# ICPS2023_5 experimental 1M routing stack for LibreLane/OpenROAD only.
# POLY and narrow TiN dimensions/R values are user-directed hypotheses, not
# foundry-qualified geometry. See libs.tech/librelane/README.md.
VERSION 5.8 ;
BUSBITCHARS "[]" ;
DIVIDERCHAR "/" ;
UNITS
  DATABASE MICRONS 1000 ;
END UNITS
MANUFACTURINGGRID 0.001 ;
# The selected row origin matches the largest published standard cell (700 um
# high); the SCL cell LEFs use this exact site name.
SITE ICPS2023_5_ROW700
  CLASS CORE ;
  SYMMETRY Y ;
  SIZE 1.0 BY 700.0 ;
END ICPS2023_5_ROW700


# LEF routing level 1. Experimental POLY-Si horizontal jumper.
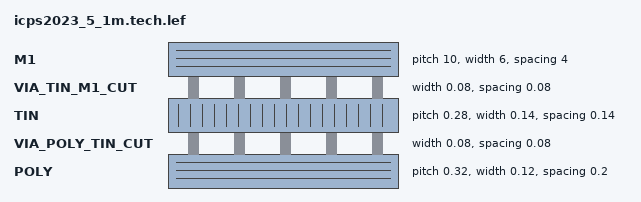
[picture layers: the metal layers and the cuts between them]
LAYER POLY
  TYPE ROUTING ;
  DIRECTION HORIZONTAL ;
  PITCH 0.32 ;
  WIDTH 0.12 ;
  SPACING 0.20 ;
  RESISTANCE RPERSQ 25.0 ;
END POLY

LAYER VIA_POLY_TIN_CUT
  TYPE CUT ;
  WIDTH 0.08 ;
  SPACING 0.08 ;
END VIA_POLY_TIN_CUT

LAYER TIN
  TYPE ROUTING ;
  DIRECTION VERTICAL ;
  PITCH 0.28 ;
  WIDTH 0.14 ;
  SPACING 0.14 ;
  RESISTANCE RPERSQ 20.0 ;
END TIN

LAYER VIA_TIN_M1_CUT
  TYPE CUT ;
  WIDTH 0.08 ;
  SPACING 0.08 ;
END VIA_TIN_M1_CUT

LAYER M1
  TYPE ROUTING ;
  DIRECTION HORIZONTAL ;
  PITCH 10.0 ;
  WIDTH 6.0 ;
  SPACING 4.0 ;
  RESISTANCE RPERSQ 0.20 ;
END M1


# Router-only experimental vias. Physical CNT remains the 5 x 5 um contact
# layer in the canonical PDK; it is not part of this single-metal router stack
# because OpenROAD treats every cut layer as a via transition.
VIA VIA_POLY_TIN DEFAULT
  LAYER POLY ;
    RECT -0.06 -0.06 0.06 0.06 ;
  LAYER VIA_POLY_TIN_CUT ;
    RECT -0.04 -0.04 0.04 0.04 ;
  LAYER TIN ;
    RECT -0.07 -0.07 0.07 0.07 ;
END VIA_POLY_TIN

# TiN<->M1 via; the 0.08 um cut is an experimental router geometry, not CNT.
VIA VIA_TIN_M1 DEFAULT
  LAYER TIN ;
    RECT -0.07 -0.07 0.07 0.07 ;
  LAYER VIA_TIN_M1_CUT ;
    RECT -0.04 -0.04 0.04 0.04 ;
  LAYER M1 ;
    RECT -3.0 -3.0 3.0 3.0 ;
END VIA_TIN_M1


END LIBRARY
